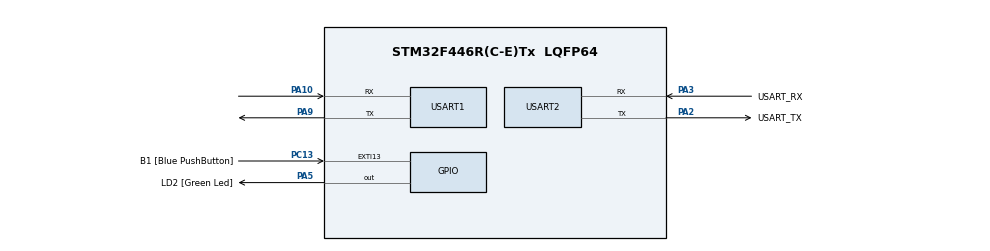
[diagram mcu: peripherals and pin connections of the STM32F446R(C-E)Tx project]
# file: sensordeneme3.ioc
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Dma.Request0=USART1_RX
Dma.USART1_RX.0.Direction=DMA_PERIPH_TO_MEMORY
Dma.USART1_RX.0.FIFOMode=DMA_FIFOMODE_DISABLE
Dma.USART1_RX.0.Instance=DMA2_Stream2
Dma.USART1_RX.0.MemDataAlignment=DMA_MDATAALIGN_BYTE
Dma.USART1_RX.0.MemInc=DMA_MINC_ENABLE
Dma.USART1_RX.0.Mode=DMA_NORMAL
Dma.USART1_RX.0.PeriphDataAlignment=DMA_PDATAALIGN_BYTE
Dma.USART1_RX.0.PeriphInc=DMA_PINC_DISABLE
Dma.USART1_RX.0.Priority=DMA_PRIORITY_LOW
Mcu.Family=STM32F4
Mcu.Name=STM32F446R(C-E)Tx
Mcu.Package=LQFP64
NVIC.DMA2_Stream2_IRQn=true\:0\:0\:false\:false\:true\:false\:true\:true
NVIC.PriorityGroup=NVIC_PRIORITYGROUP_0
NVIC.USART1_IRQn=true\:0\:0\:false\:false\:true\:true\:true\:true
PA10.Mode=Asynchronous
PA10.Signal=USART1_RX
PA13.GPIO_Label=TMS
PA13.Mode=Serial_Wire
PA13.Signal=SYS_JTMS-SWDIO
PA14.GPIO_Label=TCK
PA14.Mode=Serial_Wire
PA14.Signal=SYS_JTCK-SWCLK
PA2.GPIO_Label=USART_TX
PA2.Mode=Asynchronous
PA2.Signal=USART2_TX
PA3.GPIO_Label=USART_RX
PA3.Mode=Asynchronous
PA3.Signal=USART2_RX
PA5.GPIO_Label=LD2 [Green Led]
PA5.Signal=GPIO_Output
PA9.Mode=Asynchronous
PA9.Signal=USART1_TX
PB3.GPIO_Label=SWO
PB3.Signal=SYS_JTDO-SWO
PC13.GPIO_Label=B1 [Blue PushButton]
PC13.GPIO_ModeDefaultEXTI=GPIO_MODE_IT_FALLING
PC13.Signal=GPXTI13
PC14-OSC32_IN.Mode=LSE-External-Oscillator
PC14-OSC32_IN.Signal=RCC_OSC32_IN
PC15-OSC32_OUT.Mode=LSE-External-Oscillator
PC15-OSC32_OUT.Signal=RCC_OSC32_OUT
PH0-OSC_IN.Mode=HSE-External-Oscillator
PH0-OSC_IN.Signal=RCC_OSC_IN
PH1-OSC_OUT.Mode=HSE-External-Oscillator
PH1-OSC_OUT.Signal=RCC_OSC_OUT
ProjectManager.HeapSize=0x200
ProjectManager.StackSize=0x400
ProjectManager.TargetToolchain=STM32CubeIDE
RCC.48MHZClocksFreq_Value=84000000
RCC.AHBFreq_Value=180000000
RCC.APB1CLKDivider=RCC_HCLK_DIV4
RCC.APB1Freq_Value=45000000
RCC.APB1TimFreq_Value=90000000
RCC.APB2CLKDivider=RCC_HCLK_DIV2
RCC.APB2Freq_Value=90000000
RCC.APB2TimFreq_Value=180000000
RCC.CortexFreq_Value=180000000
RCC.FLatency-AdvancedSettings=FLASH_LATENCY_5
RCC.HCLKFreq_Value=180000000
RCC.HSE_VALUE=8000000
RCC.HSI_VALUE=16000000
RCC.PLLM=8
RCC.PLLN=180
RCC.SYSCLKFreq_VALUE=180000000
RCC.SYSCLKSource=RCC_SYSCLKSOURCE_PLLCLK
RCC.USBFreq_Value=180000000
RCC.VCOOutputFreq_Value=360000000
USART1.VirtualMode=VM_ASYNC
USART2.VirtualMode=VM_ASYNC
board=NUCLEO-F446RE

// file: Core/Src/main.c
/* USER CODE BEGIN Header */
/**
  ******************************************************************************
  * @file           : main.c
  * @brief          : Main program body
  ******************************************************************************
  * @attention
  *
  * Copyright (c) 2026 STMicroelectronics.
  * All rights reserved.
  *
  * This software is licensed under terms that can be found in the LICENSE file
  * in the root directory of this software component.
  * If no LICENSE file comes with this software, it is provided AS-IS.
  *
  ******************************************************************************
  */
/* USER CODE END Header */
#include "main.h"
#include "dma.h"
#include "usart.h"
#include "gpio.h"
#include <stdio.h>

/* USER CODE BEGIN PV */
#define RX_BUFFER_SIZE 9
uint8_t rxBuffer[RX_BUFFER_SIZE];
volatile uint8_t dataReceived = 0;

// Mesafe ve sıcaklık verileri
volatile uint16_t distance_cm = 0;
volatile uint16_t temperature_raw = 0;
/* USER CODE END PV */

void SystemClock_Config(void);

/* USER CODE BEGIN PFP */
uint16_t Calculate_CRC16(uint8_t *data, uint8_t length);
/* USER CODE END PFP */

/* USER CODE BEGIN 0 */
uint16_t Calculate_CRC16(uint8_t *data, uint8_t length)
{
    uint16_t crc = 0xFFFF;

    for (uint8_t i = 0; i < length; i++)
    {
        crc ^= (uint16_t)data[i];
        for (uint8_t j = 0; j < 8; j++)
        {
            if (crc & 0x0001)
                crc = (crc >> 1) ^ 0xA001;
            else
                crc >>= 1;
        }
    }
    return crc;
}

// UART Receive Complete Callback
void HAL_UART_RxCpltCallback(UART_HandleTypeDef *huart)
{
    if (huart->Instance == USART1)
    {
        // LED'i toggle et (yanıp söndür)
        HAL_GPIO_TogglePin(GPIOA, GPIO_PIN_5);

        // Veri doğrulama ve parse etme
        if (rxBuffer[0] == 0x01 && rxBuffer[1] == 0x04 && rxBuffer[2] == 0x04)
        {
            // Mesafe verisi (cm cinsinden)
            distance_cm = (rxBuffer[3] << 8) | rxBuffer[4];

            // Sıcaklık verisi (0.1°C cinsinden)
            temperature_raw = (rxBuffer[5] << 8) | rxBuffer[6];

            // CRC kontrolü (opsiyonel)
            uint16_t received_crc = (rxBuffer[8] << 8) | rxBuffer[7];
            uint16_t calculated_crc = Calculate_CRC16(rxBuffer, 7);

            if (received_crc == calculated_crc)
            {
                dataReceived = 1;
            }
        }

        // Bir sonraki veri için interrupt'ı tekrar başlat
        HAL_UART_Receive_IT(&huart1, rxBuffer, RX_BUFFER_SIZE);
    }
}
/* USER CODE END 0 */

int main(void)
{

  /* MCU Configuration--------------------------------------------------------*/

  /* Reset of all peripherals, Initializes the Flash interface and the Systick. */
  HAL_Init();

  /* Configure the system clock */
  SystemClock_Config();

  /* Initialize all configured peripherals */
  MX_GPIO_Init();
  MX_DMA_Init();
  MX_USART2_UART_Init();
  MX_USART1_UART_Init();
  /* USER CODE BEGIN 2 */
  HAL_GPIO_WritePin(GPIOA, GPIO_PIN_5, GPIO_PIN_RESET);

     // İlk UART receive interrupt'ını başlat
     HAL_UART_Receive_IT(&huart1, rxBuffer, RX_BUFFER_SIZE);

     HAL_Delay(500); // Sensör hazır olana kadar bekle

     // Sensörü aktif sürekli ölçüm moduna al
     // 1. Ölçüm periyodunu 50ms olarak ayarla
     uint8_t setMeasurementPeriod[] = {0x01, 0x06, 0x00, 0x42, 0x00, 0x32, 0xa8, 0x0b};
     HAL_UART_Transmit(&huart1, setMeasurementPeriod, 8, 100);
     HAL_Delay(100);

     // 2. Aktif raporlama modunu aç
     uint8_t setActiveReporting[] = {0x01, 0x06, 0x00, 0x3d, 0x00, 0x01, 0xd9, 0xc6};
     HAL_UART_Transmit(&huart1, setActiveReporting, 8, 100);
     HAL_Delay(100);

     // 3. Ölçümü başlat
     uint8_t startMeasurement[] = {0x01, 0x06, 0x00, 0x03, 0x00, 0x01, 0xb8, 0x0a};
     HAL_UART_Transmit(&huart1, startMeasurement, 8, 100);
  /* USER CODE END 2 */

  /* Infinite loop */
  while (1)
  {
	  if (dataReceived)
	          {
	              dataReceived = 0;

	              // Mesafe ve sıcaklık verilerini kullan
	              float temperature_celsius = temperature_raw / 10.0f;

	              // Örnek: Mesafe 50cm'den yakınsa LED'i hızlı yanıp söndür
	              if (distance_cm < 500) // 500 = 5 metre
	              {
	                  // Yakın mesafe - hızlı yanıp sönme
	                  HAL_Delay(50);
	              }
	              else
	              {
	                  // Uzak mesafe - normal hız
	                  HAL_Delay(200);
	              }

	              // Debug için (USART2'ye yazdırabilirsin)
	              // printf("Mesafe: %d cm, Sicaklik: %.1f C\r\n", distance_cm, temperature_celsius);
	          }

	          HAL_Delay(10);
  }
}

void SystemClock_Config(void)
{
  RCC_OscInitTypeDef RCC_OscInitStruct = {0};
  RCC_ClkInitTypeDef RCC_ClkInitStruct = {0};

  /** Configure the main internal regulator output voltage
  */
  __HAL_RCC_PWR_CLK_ENABLE();
  __HAL_PWR_VOLTAGESCALING_CONFIG(PWR_REGULATOR_VOLTAGE_SCALE3);

  /** Initializes the RCC Oscillators according to the specified parameters
  * in the RCC_OscInitTypeDef structure.
  */
  RCC_OscInitStruct.OscillatorType = RCC_OSCILLATORTYPE_HSI;
  RCC_OscInitStruct.HSIState = RCC_HSI_ON;
  RCC_OscInitStruct.HSICalibrationValue = RCC_HSICALIBRATION_DEFAULT;
  RCC_OscInitStruct.PLL.PLLState = RCC_PLL_ON;
  RCC_OscInitStruct.PLL.PLLSource = RCC_PLLSOURCE_HSI;
  RCC_OscInitStruct.PLL.PLLM = 16;
  RCC_OscInitStruct.PLL.PLLN = 336;
  RCC_OscInitStruct.PLL.PLLP = RCC_PLLP_DIV4;
  RCC_OscInitStruct.PLL.PLLQ = 2;
  RCC_OscInitStruct.PLL.PLLR = 2;
  if (HAL_RCC_OscConfig(&RCC_OscInitStruct) != HAL_OK)
  {
    Error_Handler();
  }

  /** Initializes the CPU, AHB and APB buses clocks
  */
  RCC_ClkInitStruct.ClockType = RCC_CLOCKTYPE_HCLK|RCC_CLOCKTYPE_SYSCLK
                              |RCC_CLOCKTYPE_PCLK1|RCC_CLOCKTYPE_PCLK2;
  RCC_ClkInitStruct.SYSCLKSource = RCC_SYSCLKSOURCE_PLLCLK;
  RCC_ClkInitStruct.AHBCLKDivider = RCC_SYSCLK_DIV1;
  RCC_ClkInitStruct.APB1CLKDivider = RCC_HCLK_DIV2;
  RCC_ClkInitStruct.APB2CLKDivider = RCC_HCLK_DIV1;

  if (HAL_RCC_ClockConfig(&RCC_ClkInitStruct, FLASH_LATENCY_2) != HAL_OK)
  {
    Error_Handler();
  }
}

void Error_Handler(void)
{
  __disable_irq();
  while (1)
  {
  }
}
